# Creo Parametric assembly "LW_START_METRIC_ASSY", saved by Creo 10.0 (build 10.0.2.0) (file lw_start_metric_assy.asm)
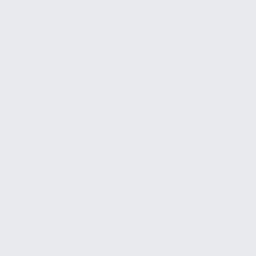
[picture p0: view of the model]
Units: hd_metric; MM, KILOGRAM, SECS

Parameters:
  DRW_UNITS = "METRIC"
  LINEAR_TOL_0 = "1.0"
  MATERIAL = "N/A"
  SUR = "6.3"
  TOL_NAME = "MILLIMETERS"
  PTC_WM_VERSION = "A.0"
  PTC_WM_CREATED_ON = "18-Apr-22 02:46:01 PM"
  PTC_WM_MODIFIED_ON = "18-Apr-22 02:46:02 PM"
  PTC_WM_NAME = "lw_start_metric_assy.asm"
  PTC_WM_NUMBER = "LW_START_METRIC_ASSY.ASM"
  PTC_WM_LIFECYCLE_STATE = "Concept"
  PTC_WM_LIFECYCLE = "HD CAD Object"
  PTC_WM_REVISION = "A"
  PTC_WM_CREATED_BY = "Graham, Jason (grahamj1: Harley-Davidson Motor Company)"
  PTC_WM_MODIFIED_BY = "Graham, Jason (grahamj1: Harley-Davidson Motor Company)"
  PTC_WM_LOCATION = "/Libraries/Library Templates/CAD/Assemblies"

Created from: HD_START_METRIC_ASSY.ASM

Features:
  1. datum plane "ASIDE"
  2. datum plane "ATOP"
  3. datum plane "AFRONT"
  4. coordinate system
  5. datum point "APT_ORIG"

Other named items: ACS_DEF, CONFIDENTIALITY_STATEMENT, COMB0001, CONFIDENTIALITY, ANNOT_LAYER_STATE0001, ANNOT_LAYER_STATE0002

Notes: THIS CAD DOCUMENT AND ALL INFORMATION DISCLOSED  | HEREIN ARE THE EXCLUSIVE PROPERTY OF  | LIVEWIRE EV, LLC ("LIVEWIRE"), AND ARE  | SUBMITTED TO THE RECIPIENT ONLY ON A CONFIDENTIAL  | BASIS. IN CONSIDERATION OF  | RECEIVING THIS CAD DOCUMENT, THE RECIPIENT AGREES: (1) NOT TO  | USE THIS CAD DOCUMENT OR ANY OF THE INFORMATION DISCLOSED HEREIN TO PRODUCE ANY  | PRODUCT OR  | FOR ANY OTHER PURPOSE EXCEPT AS AUTHORIZED IN WRITING BY LIVEWIRE; (2) NOT TO  | REPRODUCE THIS CAD DOCUMENT; (3) TO RETURN THIS CAD DOCUMENT TO LIVEWIRE UPON  | REQUEST;  | AND (4) THAT NO DISCLOSURE OF THIS CAD DOCUMENT OR ANY OF THE  | INFORMATION DISCLOSED   | HEREIN WILL BE MADE TO ANY THIRD PARTY WITHOUT THE PRIOR  | WRITTEN CONSENT OF LIVEWIRE.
